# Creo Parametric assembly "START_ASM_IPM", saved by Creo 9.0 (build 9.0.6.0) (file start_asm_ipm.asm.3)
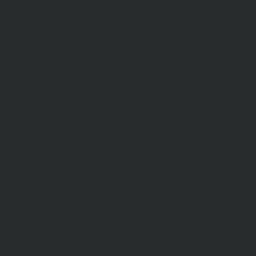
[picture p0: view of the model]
Units: IPM (mmkgsecC); MM, KILOGRAM, SECS

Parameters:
  CISLO_VYKRESU = "START_ASM_IPM"

Other parameters: HMOTNOST

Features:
  1. datum plane "ASM_BOKORYS"
  2. datum plane "ASM_PODORYS"
  3. datum plane "ASM_NARYS"
  4. coordinate system

Other named items: ASM_KSYS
